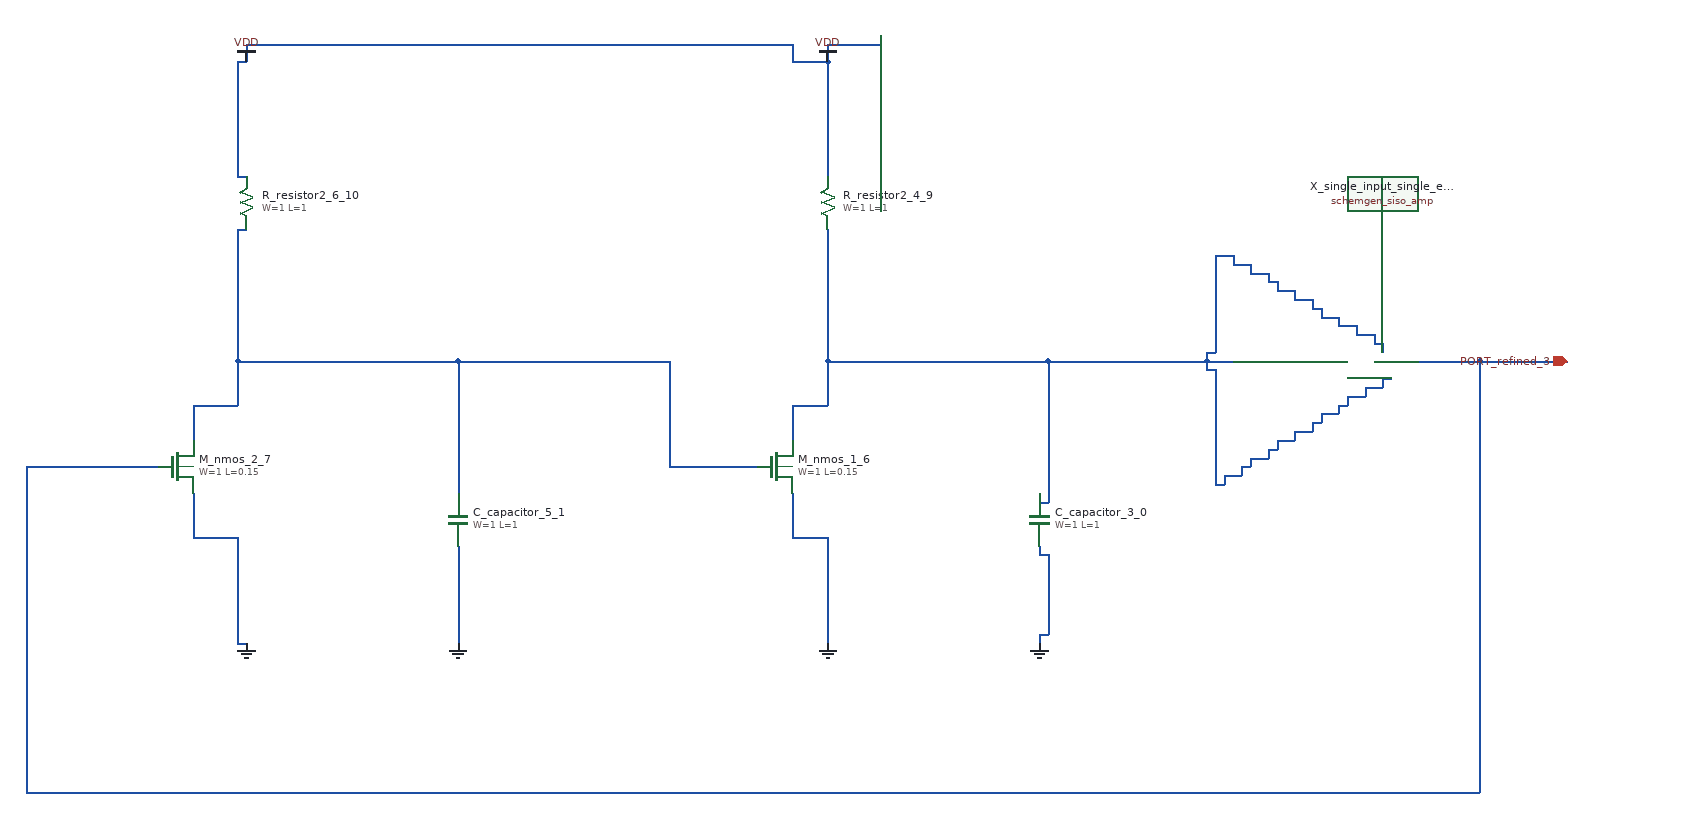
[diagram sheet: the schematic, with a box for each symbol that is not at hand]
v {xschem version=3.4.8 file_version=1.2}
G {}
K {}
V {}
S {}
E {}
C {sky130_fd_pr/cap_mim_m3_1.sym} 1240 640 0 0 {name="C_capacitor_3_0" model=cap_mim_m3_1 W=1 L=1 MF=1 spiceprefix=X}
C {sky130_fd_pr/cap_mim_m3_1.sym} 580 640 0 0 {name="C_capacitor_5_1" model=cap_mim_m3_1 W=1 L=1 MF=1 spiceprefix=X}
C {devices/gnd.sym} 1000 780 0 0 {name="l_gnd_10_2" lab="GND"}
C {devices/gnd.sym} 340 780 0 0 {name="l_gnd_7_3" lab="GND"}
C {devices/gnd.sym} 1240 780 0 0 {name="l_gnd_8_4" lab="GND"}
C {devices/gnd.sym} 580 780 0 0 {name="l_gnd_9_5" lab="GND"}
C {sky130_fd_pr/nfet3_01v8.sym} 940 580 0 0 {name="M_nmos_1_6"
W=1
L=0.15
body=GND
nf=1
mult=1
ad="expr('int((@nf + 1)/2) * @W / @nf * 0.29')"
pd="expr('2*int((@nf + 1)/2) * (@W / @nf + 0.29)')"
as="expr('int((@nf + 2)/2) * @W / @nf * 0.29')"
ps="expr('2*int((@nf + 2)/2) * (@W / @nf + 0.29)')"
nrd="expr('0.29 / @W ')" nrs="expr('0.29 / @W ')"
sa=0 sb=0 sd=0
model=nfet_01v8
spiceprefix=X
}
C {sky130_fd_pr/nfet3_01v8.sym} 260 580 0 0 {name="M_nmos_2_7"
W=1
L=0.15
body=GND
nf=1
mult=1
ad="expr('int((@nf + 1)/2) * @W / @nf * 0.29')"
pd="expr('2*int((@nf + 1)/2) * (@W / @nf + 0.29)')"
as="expr('int((@nf + 2)/2) * @W / @nf * 0.29')"
ps="expr('2*int((@nf + 2)/2) * (@W / @nf + 0.29)')"
nrd="expr('0.29 / @W ')" nrs="expr('0.29 / @W ')"
sa=0 sb=0 sd=0
model=nfet_01v8
spiceprefix=X
}
C {devices/ipin.sym} 1840 460 0 0 {name="p_port_11_8" lab="PORT_refined_3"}
C {sky130_fd_pr/res_generic_po.sym} 1000 280 2 0 {name="R_resistor2_4_9"
W=1
L=1
model=res_generic_po
spiceprefix=X
mult=1}
C {sky130_fd_pr/res_generic_po.sym} 340 280 2 0 {name="R_resistor2_6_10"
W=1
L=1
model=res_generic_po
spiceprefix=X
mult=1}
C {schemgen_siso_amp.sym} 1540 460 0 0 {name="X_single_input_single_end_amp_14_11"}
C {devices/vdd.sym} 1000 120 0 0 {name="l_vdd_12_12" lab="VDD"}
C {devices/vdd.sym} 340 120 0 0 {name="l_vdd_13_13" lab="VDD"}
N 330 780 340 780 {}
N 1240 770 1250 770 {}
N 1240 680 1250 680 {}
N 280 660 330 660 {}
N 960 660 1000 660 {}
N 280 660 280 610 {}
N 330 780 330 660 {}
N 580 780 580 670 {}
N 960 660 960 610 {}
N 1000 780 1000 660 {}
N 1240 780 1240 770 {}
N 1240 680 1240 670 {}
N 1250 770 1250 680 {}
N 1240 620 1250 620 {}
N 1440 600 1450 600 {}
N 1450 590 1470 590 {}
N 1470 580 1480 580 {}
N 1480 570 1500 570 {}
N 1500 560 1510 560 {}
N 1510 550 1530 550 {}
N 1530 540 1550 540 {}
N 1550 530 1560 530 {}
N 1560 520 1580 520 {}
N 960 510 1000 510 {}
N 1580 510 1590 510 {}
N 1590 500 1610 500 {}
N 1610 490 1630 490 {}
N 1630 480 1640 480 {}
N 1430 470 1440 470 {}
N 1000 460 1250 460 {}
N 1250 460 1430 460 {}
N 1430 460 1460 460 {}
N 1430 450 1440 450 {}
N 1620 440 1630 440 {}
N 1600 430 1620 430 {}
N 1580 420 1600 420 {}
N 1560 410 1580 410 {}
N 1550 400 1560 400 {}
N 1530 390 1550 390 {}
N 1510 380 1530 380 {}
N 1500 370 1510 370 {}
N 1480 360 1500 360 {}
N 1460 350 1480 350 {}
N 1440 340 1460 340 {}
N 960 550 960 510 {}
N 1000 510 1000 460 {}
N 1000 460 1000 310 {}
N 1240 620 1240 610 {}
N 1250 620 1250 460 {}
N 1430 470 1430 460 {}
N 1430 460 1430 450 {}
N 1440 600 1440 470 {}
N 1440 450 1440 340 {}
N 1450 600 1450 590 {}
N 1460 350 1460 340 {}
N 1470 590 1470 580 {}
N 1480 580 1480 570 {}
N 1480 360 1480 350 {}
N 1500 570 1500 560 {}
N 1500 370 1500 360 {}
N 1510 560 1510 550 {}
N 1510 380 1510 370 {}
N 1530 550 1530 540 {}
N 1530 390 1530 380 {}
N 1550 540 1550 530 {}
N 1550 400 1550 390 {}
N 1560 530 1560 520 {}
N 1560 410 1560 400 {}
N 1580 520 1580 510 {}
N 1580 420 1580 410 {}
N 1590 510 1590 500 {}
N 1600 430 1600 420 {}
N 1610 500 1610 490 {}
N 1620 440 1620 430 {}
N 1630 490 1630 480 {}
N 1630 450 1630 440 {}
N 820 580 920 580 {}
N 280 510 330 510 {}
N 330 460 580 460 {}
N 580 460 820 460 {}
N 330 310 340 310 {}
N 280 550 280 510 {}
N 330 510 330 460 {}
N 330 460 330 310 {}
N 580 620 580 610 {}
N 580 610 580 460 {}
N 820 580 820 460 {}
N 90 950 1740 950 {}
N 90 580 240 580 {}
N 1620 460 1740 460 {}
N 1740 460 1840 460 {}
N 90 950 90 580 {}
N 1740 950 1740 460 {}
N 330 250 340 250 {}
N 330 120 340 120 {}
N 960 120 1000 120 {}
N 340 100 960 100 {}
N 1000 100 1060 100 {}
N 330 250 330 120 {}
N 340 120 340 100 {}
N 960 120 960 100 {}
N 1000 250 1000 120 {}
N 1000 120 1000 100 {}
N 1060 100 1060 90 {}
